VERSION 5.7 ;
  NOWIREEXTENSIONATPIN ON ;
  DIVIDERCHAR "/" ;
  BUSBITCHARS "[]" ;
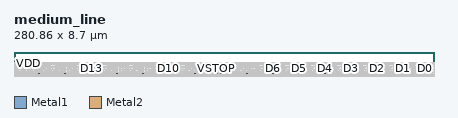
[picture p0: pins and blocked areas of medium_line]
MACRO medium_line
  CLASS BLOCK ;
  FOREIGN medium_line ;
  ORIGIN 0.430 0.430 ;
  SIZE 280.860 BY 8.700 ;
  PIN VSTART
    ANTENNAGATEAREA 0.396000 ;
    PORT
      LAYER Metal1 ;
        RECT 2.200 5.140 4.300 5.500 ;
    END
  END VSTART
  PIN D15
    ANTENNADIFFAREA 0.897600 ;
    PORT
      LAYER Metal1 ;
        RECT 16.200 1.070 16.600 1.470 ;
    END
  END D15
  PIN D14
    ANTENNADIFFAREA 0.897600 ;
    PORT
      LAYER Metal1 ;
        RECT 33.560 1.070 33.960 1.470 ;
    END
  END D14
  PIN D13
    ANTENNADIFFAREA 0.897600 ;
    PORT
      LAYER Metal1 ;
        RECT 50.920 1.070 51.320 1.470 ;
    END
  END D13
  PIN D12
    ANTENNADIFFAREA 0.897600 ;
    PORT
      LAYER Metal1 ;
        RECT 68.280 1.070 68.680 1.470 ;
    END
  END D12
  PIN D11
    ANTENNADIFFAREA 0.897600 ;
    PORT
      LAYER Metal1 ;
        RECT 85.640 1.070 86.040 1.470 ;
    END
  END D11
  PIN D10
    ANTENNADIFFAREA 0.897600 ;
    PORT
      LAYER Metal1 ;
        RECT 103.000 1.070 103.400 1.470 ;
    END
  END D10
  PIN D9
    ANTENNADIFFAREA 0.897600 ;
    PORT
      LAYER Metal1 ;
        RECT 120.360 1.070 120.760 1.470 ;
    END
  END D9
  PIN D8
    ANTENNADIFFAREA 0.897600 ;
    PORT
      LAYER Metal1 ;
        RECT 137.720 1.070 138.120 1.470 ;
    END
  END D8
  PIN D7
    ANTENNADIFFAREA 0.897600 ;
    PORT
      LAYER Metal1 ;
        RECT 155.080 1.070 155.480 1.470 ;
    END
  END D7
  PIN D6
    ANTENNADIFFAREA 0.897600 ;
    PORT
      LAYER Metal1 ;
        RECT 172.440 1.070 172.840 1.470 ;
    END
  END D6
  PIN D5
    ANTENNADIFFAREA 0.897600 ;
    PORT
      LAYER Metal1 ;
        RECT 189.800 1.070 190.200 1.470 ;
    END
  END D5
  PIN D4
    ANTENNADIFFAREA 0.897600 ;
    PORT
      LAYER Metal1 ;
        RECT 207.160 1.070 207.560 1.470 ;
    END
  END D4
  PIN D3
    ANTENNADIFFAREA 0.897600 ;
    PORT
      LAYER Metal1 ;
        RECT 224.520 1.070 224.920 1.470 ;
    END
  END D3
  PIN D2
    ANTENNADIFFAREA 0.897600 ;
    PORT
      LAYER Metal1 ;
        RECT 241.880 1.070 242.280 1.470 ;
    END
  END D2
  PIN D1
    ANTENNADIFFAREA 0.897600 ;
    PORT
      LAYER Metal1 ;
        RECT 259.240 1.070 259.640 1.470 ;
    END
  END D1
  PIN D0
    ANTENNADIFFAREA 0.897600 ;
    PORT
      LAYER Metal1 ;
        RECT 276.600 1.070 277.000 1.470 ;
    END
  END D0
  PIN VSTOP
    ANTENNAGATEAREA 10.808000 ;
    PORT
      LAYER Metal2 ;
        RECT 135.000 1.500 135.400 1.720 ;
    END
  END VSTOP
  PIN VDD
    USE POWER ;
    PORT
      LAYER Metal1 ;
        RECT 5.000 7.740 5.400 8.040 ;
    END
  END VDD
  PIN VSS
    USE GROUND ;
    PORT
      LAYER Metal1 ;
        RECT 5.000 3.720 5.400 4.120 ;
    END
  END VSS
  OBS
      LAYER Nwell ;
        RECT -0.430 5.680 280.430 8.270 ;
      LAYER Pwell ;
        RECT -0.430 2.160 280.430 5.680 ;
      LAYER Nwell ;
        RECT -0.430 2.035 5.985 2.160 ;
      LAYER Pwell ;
        RECT 5.985 2.035 7.240 2.160 ;
      LAYER Nwell ;
        RECT 7.240 2.035 23.345 2.160 ;
      LAYER Pwell ;
        RECT 23.345 2.035 24.600 2.160 ;
      LAYER Nwell ;
        RECT 24.600 2.035 40.705 2.160 ;
      LAYER Pwell ;
        RECT 40.705 2.035 41.960 2.160 ;
      LAYER Nwell ;
        RECT 41.960 2.035 58.065 2.160 ;
      LAYER Pwell ;
        RECT 58.065 2.035 59.320 2.160 ;
      LAYER Nwell ;
        RECT 59.320 2.035 75.425 2.160 ;
      LAYER Pwell ;
        RECT 75.425 2.035 76.680 2.160 ;
      LAYER Nwell ;
        RECT 76.680 2.035 92.785 2.160 ;
      LAYER Pwell ;
        RECT 92.785 2.035 94.040 2.160 ;
      LAYER Nwell ;
        RECT 94.040 2.035 110.145 2.160 ;
      LAYER Pwell ;
        RECT 110.145 2.035 111.400 2.160 ;
      LAYER Nwell ;
        RECT 111.400 2.035 127.505 2.160 ;
      LAYER Pwell ;
        RECT 127.505 2.035 128.760 2.160 ;
      LAYER Nwell ;
        RECT 128.760 2.035 144.865 2.160 ;
      LAYER Pwell ;
        RECT 144.865 2.035 146.120 2.160 ;
      LAYER Nwell ;
        RECT 146.120 2.035 162.225 2.160 ;
      LAYER Pwell ;
        RECT 162.225 2.035 163.480 2.160 ;
      LAYER Nwell ;
        RECT 163.480 2.035 179.585 2.160 ;
      LAYER Pwell ;
        RECT 179.585 2.035 180.840 2.160 ;
      LAYER Nwell ;
        RECT 180.840 2.035 196.945 2.160 ;
      LAYER Pwell ;
        RECT 196.945 2.035 198.200 2.160 ;
      LAYER Nwell ;
        RECT 198.200 2.035 214.305 2.160 ;
      LAYER Pwell ;
        RECT 214.305 2.035 215.560 2.160 ;
      LAYER Nwell ;
        RECT 215.560 2.035 231.665 2.160 ;
      LAYER Pwell ;
        RECT 231.665 2.035 232.920 2.160 ;
      LAYER Nwell ;
        RECT 232.920 2.035 249.025 2.160 ;
      LAYER Pwell ;
        RECT 249.025 2.035 250.280 2.160 ;
      LAYER Nwell ;
        RECT 250.280 2.035 266.385 2.160 ;
      LAYER Pwell ;
        RECT 266.385 2.035 267.640 2.160 ;
      LAYER Nwell ;
        RECT 267.640 2.035 280.430 2.160 ;
        RECT -0.430 -0.430 280.430 2.035 ;
      LAYER Metal1 ;
        RECT 0.000 8.040 280.000 8.140 ;
        RECT 0.000 7.740 5.000 8.040 ;
        RECT 5.400 7.740 280.000 8.040 ;
        RECT 0.000 7.540 280.000 7.740 ;
        RECT 0.370 5.840 0.710 7.540 ;
        RECT 2.580 7.205 2.920 7.540 ;
        RECT 7.560 7.205 7.900 7.540 ;
        RECT 12.840 7.095 13.180 7.540 ;
        RECT 1.340 6.325 1.680 7.025 ;
        RECT 1.340 5.985 4.360 6.325 ;
        RECT 0.370 4.220 0.710 5.110 ;
        RECT 1.340 4.590 1.680 5.985 ;
        RECT 4.815 5.725 5.045 7.080 ;
        RECT 5.480 6.795 6.885 7.025 ;
        RECT 2.025 5.500 4.450 5.520 ;
        RECT 2.025 5.140 2.200 5.500 ;
        RECT 4.300 5.140 4.450 5.500 ;
        RECT 2.025 5.120 4.450 5.140 ;
        RECT 4.815 5.385 6.425 5.725 ;
        RECT 6.655 5.670 6.885 6.795 ;
        RECT 9.995 5.885 10.380 7.080 ;
        RECT 10.815 6.385 11.045 7.080 ;
        RECT 14.490 6.630 14.875 7.115 ;
        RECT 10.815 6.155 12.785 6.385 ;
        RECT 13.085 6.250 14.875 6.630 ;
        RECT 6.655 5.440 9.210 5.670 ;
        RECT 9.995 5.455 12.175 5.885 ;
        RECT 12.465 5.545 12.785 6.155 ;
        RECT 4.815 4.690 5.200 5.385 ;
        RECT 6.655 4.920 6.885 5.440 ;
        RECT 5.580 4.690 6.885 4.920 ;
        RECT 9.995 4.635 10.225 5.455 ;
        RECT 12.465 5.315 14.250 5.545 ;
        RECT 12.465 4.975 12.785 5.315 ;
        RECT 10.815 4.635 12.785 4.975 ;
        RECT 2.680 4.220 3.020 4.555 ;
        RECT 7.760 4.220 8.100 4.555 ;
        RECT 13.235 4.220 13.465 4.610 ;
        RECT 14.645 4.595 14.875 6.250 ;
        RECT 15.510 5.850 15.850 7.540 ;
        RECT 16.630 5.850 16.970 7.540 ;
        RECT 17.750 5.850 18.090 7.540 ;
        RECT 19.940 7.205 20.280 7.540 ;
        RECT 24.920 7.205 25.260 7.540 ;
        RECT 30.200 7.095 30.540 7.540 ;
        RECT 18.700 6.325 19.040 7.025 ;
        RECT 18.700 5.985 21.720 6.325 ;
        RECT 15.510 4.220 15.850 5.105 ;
        RECT 16.630 4.220 16.970 5.105 ;
        RECT 17.750 4.220 18.090 5.105 ;
        RECT 18.700 4.590 19.040 5.985 ;
        RECT 22.175 5.725 22.405 7.080 ;
        RECT 22.840 6.795 24.245 7.025 ;
        RECT 19.385 5.120 21.810 5.520 ;
        RECT 22.175 5.385 23.785 5.725 ;
        RECT 24.015 5.670 24.245 6.795 ;
        RECT 27.355 5.885 27.740 7.080 ;
        RECT 28.175 6.385 28.405 7.080 ;
        RECT 31.850 6.630 32.235 7.115 ;
        RECT 28.175 6.155 30.145 6.385 ;
        RECT 30.445 6.250 32.235 6.630 ;
        RECT 24.015 5.440 26.570 5.670 ;
        RECT 27.355 5.455 29.535 5.885 ;
        RECT 29.825 5.545 30.145 6.155 ;
        RECT 22.175 4.690 22.560 5.385 ;
        RECT 24.015 4.920 24.245 5.440 ;
        RECT 22.940 4.690 24.245 4.920 ;
        RECT 27.355 4.635 27.585 5.455 ;
        RECT 29.825 5.315 31.610 5.545 ;
        RECT 29.825 4.975 30.145 5.315 ;
        RECT 28.175 4.635 30.145 4.975 ;
        RECT 20.040 4.220 20.380 4.555 ;
        RECT 25.120 4.220 25.460 4.555 ;
        RECT 30.595 4.220 30.825 4.610 ;
        RECT 32.005 4.595 32.235 6.250 ;
        RECT 32.870 5.850 33.210 7.540 ;
        RECT 33.990 5.850 34.330 7.540 ;
        RECT 35.110 5.850 35.450 7.540 ;
        RECT 37.300 7.205 37.640 7.540 ;
        RECT 42.280 7.205 42.620 7.540 ;
        RECT 47.560 7.095 47.900 7.540 ;
        RECT 36.060 6.325 36.400 7.025 ;
        RECT 36.060 5.985 39.080 6.325 ;
        RECT 32.870 4.220 33.210 5.105 ;
        RECT 33.990 4.220 34.330 5.105 ;
        RECT 35.110 4.220 35.450 5.105 ;
        RECT 36.060 4.590 36.400 5.985 ;
        RECT 39.535 5.725 39.765 7.080 ;
        RECT 40.200 6.795 41.605 7.025 ;
        RECT 36.745 5.120 39.170 5.520 ;
        RECT 39.535 5.385 41.145 5.725 ;
        RECT 41.375 5.670 41.605 6.795 ;
        RECT 44.715 5.885 45.100 7.080 ;
        RECT 45.535 6.385 45.765 7.080 ;
        RECT 49.210 6.630 49.595 7.115 ;
        RECT 45.535 6.155 47.505 6.385 ;
        RECT 47.805 6.250 49.595 6.630 ;
        RECT 41.375 5.440 43.930 5.670 ;
        RECT 44.715 5.455 46.895 5.885 ;
        RECT 47.185 5.545 47.505 6.155 ;
        RECT 39.535 4.690 39.920 5.385 ;
        RECT 41.375 4.920 41.605 5.440 ;
        RECT 40.300 4.690 41.605 4.920 ;
        RECT 44.715 4.635 44.945 5.455 ;
        RECT 47.185 5.315 48.970 5.545 ;
        RECT 47.185 4.975 47.505 5.315 ;
        RECT 45.535 4.635 47.505 4.975 ;
        RECT 37.400 4.220 37.740 4.555 ;
        RECT 42.480 4.220 42.820 4.555 ;
        RECT 47.955 4.220 48.185 4.610 ;
        RECT 49.365 4.595 49.595 6.250 ;
        RECT 50.230 5.850 50.570 7.540 ;
        RECT 51.350 5.850 51.690 7.540 ;
        RECT 52.470 5.850 52.810 7.540 ;
        RECT 54.660 7.205 55.000 7.540 ;
        RECT 59.640 7.205 59.980 7.540 ;
        RECT 64.920 7.095 65.260 7.540 ;
        RECT 53.420 6.325 53.760 7.025 ;
        RECT 53.420 5.985 56.440 6.325 ;
        RECT 50.230 4.220 50.570 5.105 ;
        RECT 51.350 4.220 51.690 5.105 ;
        RECT 52.470 4.220 52.810 5.105 ;
        RECT 53.420 4.590 53.760 5.985 ;
        RECT 56.895 5.725 57.125 7.080 ;
        RECT 57.560 6.795 58.965 7.025 ;
        RECT 54.105 5.120 56.530 5.520 ;
        RECT 56.895 5.385 58.505 5.725 ;
        RECT 58.735 5.670 58.965 6.795 ;
        RECT 62.075 5.885 62.460 7.080 ;
        RECT 62.895 6.385 63.125 7.080 ;
        RECT 66.570 6.630 66.955 7.115 ;
        RECT 62.895 6.155 64.865 6.385 ;
        RECT 65.165 6.250 66.955 6.630 ;
        RECT 58.735 5.440 61.290 5.670 ;
        RECT 62.075 5.455 64.255 5.885 ;
        RECT 64.545 5.545 64.865 6.155 ;
        RECT 56.895 4.690 57.280 5.385 ;
        RECT 58.735 4.920 58.965 5.440 ;
        RECT 57.660 4.690 58.965 4.920 ;
        RECT 62.075 4.635 62.305 5.455 ;
        RECT 64.545 5.315 66.330 5.545 ;
        RECT 64.545 4.975 64.865 5.315 ;
        RECT 62.895 4.635 64.865 4.975 ;
        RECT 54.760 4.220 55.100 4.555 ;
        RECT 59.840 4.220 60.180 4.555 ;
        RECT 65.315 4.220 65.545 4.610 ;
        RECT 66.725 4.595 66.955 6.250 ;
        RECT 67.590 5.850 67.930 7.540 ;
        RECT 68.710 5.850 69.050 7.540 ;
        RECT 69.830 5.850 70.170 7.540 ;
        RECT 72.020 7.205 72.360 7.540 ;
        RECT 77.000 7.205 77.340 7.540 ;
        RECT 82.280 7.095 82.620 7.540 ;
        RECT 70.780 6.325 71.120 7.025 ;
        RECT 70.780 5.985 73.800 6.325 ;
        RECT 67.590 4.220 67.930 5.105 ;
        RECT 68.710 4.220 69.050 5.105 ;
        RECT 69.830 4.220 70.170 5.105 ;
        RECT 70.780 4.590 71.120 5.985 ;
        RECT 74.255 5.725 74.485 7.080 ;
        RECT 74.920 6.795 76.325 7.025 ;
        RECT 71.465 5.120 73.890 5.520 ;
        RECT 74.255 5.385 75.865 5.725 ;
        RECT 76.095 5.670 76.325 6.795 ;
        RECT 79.435 5.885 79.820 7.080 ;
        RECT 80.255 6.385 80.485 7.080 ;
        RECT 83.930 6.630 84.315 7.115 ;
        RECT 80.255 6.155 82.225 6.385 ;
        RECT 82.525 6.250 84.315 6.630 ;
        RECT 76.095 5.440 78.650 5.670 ;
        RECT 79.435 5.455 81.615 5.885 ;
        RECT 81.905 5.545 82.225 6.155 ;
        RECT 74.255 4.690 74.640 5.385 ;
        RECT 76.095 4.920 76.325 5.440 ;
        RECT 75.020 4.690 76.325 4.920 ;
        RECT 79.435 4.635 79.665 5.455 ;
        RECT 81.905 5.315 83.690 5.545 ;
        RECT 81.905 4.975 82.225 5.315 ;
        RECT 80.255 4.635 82.225 4.975 ;
        RECT 72.120 4.220 72.460 4.555 ;
        RECT 77.200 4.220 77.540 4.555 ;
        RECT 82.675 4.220 82.905 4.610 ;
        RECT 84.085 4.595 84.315 6.250 ;
        RECT 84.950 5.850 85.290 7.540 ;
        RECT 86.070 5.850 86.410 7.540 ;
        RECT 87.190 5.850 87.530 7.540 ;
        RECT 89.380 7.205 89.720 7.540 ;
        RECT 94.360 7.205 94.700 7.540 ;
        RECT 99.640 7.095 99.980 7.540 ;
        RECT 88.140 6.325 88.480 7.025 ;
        RECT 88.140 5.985 91.160 6.325 ;
        RECT 84.950 4.220 85.290 5.105 ;
        RECT 86.070 4.220 86.410 5.105 ;
        RECT 87.190 4.220 87.530 5.105 ;
        RECT 88.140 4.590 88.480 5.985 ;
        RECT 91.615 5.725 91.845 7.080 ;
        RECT 92.280 6.795 93.685 7.025 ;
        RECT 88.825 5.120 91.250 5.520 ;
        RECT 91.615 5.385 93.225 5.725 ;
        RECT 93.455 5.670 93.685 6.795 ;
        RECT 96.795 5.885 97.180 7.080 ;
        RECT 97.615 6.385 97.845 7.080 ;
        RECT 101.290 6.630 101.675 7.115 ;
        RECT 97.615 6.155 99.585 6.385 ;
        RECT 99.885 6.250 101.675 6.630 ;
        RECT 93.455 5.440 96.010 5.670 ;
        RECT 96.795 5.455 98.975 5.885 ;
        RECT 99.265 5.545 99.585 6.155 ;
        RECT 91.615 4.690 92.000 5.385 ;
        RECT 93.455 4.920 93.685 5.440 ;
        RECT 92.380 4.690 93.685 4.920 ;
        RECT 96.795 4.635 97.025 5.455 ;
        RECT 99.265 5.315 101.050 5.545 ;
        RECT 99.265 4.975 99.585 5.315 ;
        RECT 97.615 4.635 99.585 4.975 ;
        RECT 89.480 4.220 89.820 4.555 ;
        RECT 94.560 4.220 94.900 4.555 ;
        RECT 100.035 4.220 100.265 4.610 ;
        RECT 101.445 4.595 101.675 6.250 ;
        RECT 102.310 5.850 102.650 7.540 ;
        RECT 103.430 5.850 103.770 7.540 ;
        RECT 104.550 5.850 104.890 7.540 ;
        RECT 106.740 7.205 107.080 7.540 ;
        RECT 111.720 7.205 112.060 7.540 ;
        RECT 117.000 7.095 117.340 7.540 ;
        RECT 105.500 6.325 105.840 7.025 ;
        RECT 105.500 5.985 108.520 6.325 ;
        RECT 102.310 4.220 102.650 5.105 ;
        RECT 103.430 4.220 103.770 5.105 ;
        RECT 104.550 4.220 104.890 5.105 ;
        RECT 105.500 4.590 105.840 5.985 ;
        RECT 108.975 5.725 109.205 7.080 ;
        RECT 109.640 6.795 111.045 7.025 ;
        RECT 106.185 5.120 108.610 5.520 ;
        RECT 108.975 5.385 110.585 5.725 ;
        RECT 110.815 5.670 111.045 6.795 ;
        RECT 114.155 5.885 114.540 7.080 ;
        RECT 114.975 6.385 115.205 7.080 ;
        RECT 118.650 6.630 119.035 7.115 ;
        RECT 114.975 6.155 116.945 6.385 ;
        RECT 117.245 6.250 119.035 6.630 ;
        RECT 110.815 5.440 113.370 5.670 ;
        RECT 114.155 5.455 116.335 5.885 ;
        RECT 116.625 5.545 116.945 6.155 ;
        RECT 108.975 4.690 109.360 5.385 ;
        RECT 110.815 4.920 111.045 5.440 ;
        RECT 109.740 4.690 111.045 4.920 ;
        RECT 114.155 4.635 114.385 5.455 ;
        RECT 116.625 5.315 118.410 5.545 ;
        RECT 116.625 4.975 116.945 5.315 ;
        RECT 114.975 4.635 116.945 4.975 ;
        RECT 106.840 4.220 107.180 4.555 ;
        RECT 111.920 4.220 112.260 4.555 ;
        RECT 117.395 4.220 117.625 4.610 ;
        RECT 118.805 4.595 119.035 6.250 ;
        RECT 119.670 5.850 120.010 7.540 ;
        RECT 120.790 5.850 121.130 7.540 ;
        RECT 121.910 5.850 122.250 7.540 ;
        RECT 124.100 7.205 124.440 7.540 ;
        RECT 129.080 7.205 129.420 7.540 ;
        RECT 134.360 7.095 134.700 7.540 ;
        RECT 122.860 6.325 123.200 7.025 ;
        RECT 122.860 5.985 125.880 6.325 ;
        RECT 119.670 4.220 120.010 5.105 ;
        RECT 120.790 4.220 121.130 5.105 ;
        RECT 121.910 4.220 122.250 5.105 ;
        RECT 122.860 4.590 123.200 5.985 ;
        RECT 126.335 5.725 126.565 7.080 ;
        RECT 127.000 6.795 128.405 7.025 ;
        RECT 123.545 5.120 125.970 5.520 ;
        RECT 126.335 5.385 127.945 5.725 ;
        RECT 128.175 5.670 128.405 6.795 ;
        RECT 131.515 5.885 131.900 7.080 ;
        RECT 132.335 6.385 132.565 7.080 ;
        RECT 136.010 6.630 136.395 7.115 ;
        RECT 132.335 6.155 134.305 6.385 ;
        RECT 134.605 6.250 136.395 6.630 ;
        RECT 128.175 5.440 130.730 5.670 ;
        RECT 131.515 5.455 133.695 5.885 ;
        RECT 133.985 5.545 134.305 6.155 ;
        RECT 126.335 4.690 126.720 5.385 ;
        RECT 128.175 4.920 128.405 5.440 ;
        RECT 127.100 4.690 128.405 4.920 ;
        RECT 131.515 4.635 131.745 5.455 ;
        RECT 133.985 5.315 135.770 5.545 ;
        RECT 133.985 4.975 134.305 5.315 ;
        RECT 132.335 4.635 134.305 4.975 ;
        RECT 124.200 4.220 124.540 4.555 ;
        RECT 129.280 4.220 129.620 4.555 ;
        RECT 134.755 4.220 134.985 4.610 ;
        RECT 136.165 4.595 136.395 6.250 ;
        RECT 137.030 5.850 137.370 7.540 ;
        RECT 138.150 5.850 138.490 7.540 ;
        RECT 139.270 5.850 139.610 7.540 ;
        RECT 141.460 7.205 141.800 7.540 ;
        RECT 146.440 7.205 146.780 7.540 ;
        RECT 151.720 7.095 152.060 7.540 ;
        RECT 140.220 6.325 140.560 7.025 ;
        RECT 140.220 5.985 143.240 6.325 ;
        RECT 137.030 4.220 137.370 5.105 ;
        RECT 138.150 4.220 138.490 5.105 ;
        RECT 139.270 4.220 139.610 5.105 ;
        RECT 140.220 4.590 140.560 5.985 ;
        RECT 143.695 5.725 143.925 7.080 ;
        RECT 144.360 6.795 145.765 7.025 ;
        RECT 140.905 5.120 143.330 5.520 ;
        RECT 143.695 5.385 145.305 5.725 ;
        RECT 145.535 5.670 145.765 6.795 ;
        RECT 148.875 5.885 149.260 7.080 ;
        RECT 149.695 6.385 149.925 7.080 ;
        RECT 153.370 6.630 153.755 7.115 ;
        RECT 149.695 6.155 151.665 6.385 ;
        RECT 151.965 6.250 153.755 6.630 ;
        RECT 145.535 5.440 148.090 5.670 ;
        RECT 148.875 5.455 151.055 5.885 ;
        RECT 151.345 5.545 151.665 6.155 ;
        RECT 143.695 4.690 144.080 5.385 ;
        RECT 145.535 4.920 145.765 5.440 ;
        RECT 144.460 4.690 145.765 4.920 ;
        RECT 148.875 4.635 149.105 5.455 ;
        RECT 151.345 5.315 153.130 5.545 ;
        RECT 151.345 4.975 151.665 5.315 ;
        RECT 149.695 4.635 151.665 4.975 ;
        RECT 141.560 4.220 141.900 4.555 ;
        RECT 146.640 4.220 146.980 4.555 ;
        RECT 152.115 4.220 152.345 4.610 ;
        RECT 153.525 4.595 153.755 6.250 ;
        RECT 154.390 5.850 154.730 7.540 ;
        RECT 155.510 5.850 155.850 7.540 ;
        RECT 156.630 5.850 156.970 7.540 ;
        RECT 158.820 7.205 159.160 7.540 ;
        RECT 163.800 7.205 164.140 7.540 ;
        RECT 169.080 7.095 169.420 7.540 ;
        RECT 157.580 6.325 157.920 7.025 ;
        RECT 157.580 5.985 160.600 6.325 ;
        RECT 154.390 4.220 154.730 5.105 ;
        RECT 155.510 4.220 155.850 5.105 ;
        RECT 156.630 4.220 156.970 5.105 ;
        RECT 157.580 4.590 157.920 5.985 ;
        RECT 161.055 5.725 161.285 7.080 ;
        RECT 161.720 6.795 163.125 7.025 ;
        RECT 158.265 5.120 160.690 5.520 ;
        RECT 161.055 5.385 162.665 5.725 ;
        RECT 162.895 5.670 163.125 6.795 ;
        RECT 166.235 5.885 166.620 7.080 ;
        RECT 167.055 6.385 167.285 7.080 ;
        RECT 170.730 6.630 171.115 7.115 ;
        RECT 167.055 6.155 169.025 6.385 ;
        RECT 169.325 6.250 171.115 6.630 ;
        RECT 162.895 5.440 165.450 5.670 ;
        RECT 166.235 5.455 168.415 5.885 ;
        RECT 168.705 5.545 169.025 6.155 ;
        RECT 161.055 4.690 161.440 5.385 ;
        RECT 162.895 4.920 163.125 5.440 ;
        RECT 161.820 4.690 163.125 4.920 ;
        RECT 166.235 4.635 166.465 5.455 ;
        RECT 168.705 5.315 170.490 5.545 ;
        RECT 168.705 4.975 169.025 5.315 ;
        RECT 167.055 4.635 169.025 4.975 ;
        RECT 158.920 4.220 159.260 4.555 ;
        RECT 164.000 4.220 164.340 4.555 ;
        RECT 169.475 4.220 169.705 4.610 ;
        RECT 170.885 4.595 171.115 6.250 ;
        RECT 171.750 5.850 172.090 7.540 ;
        RECT 172.870 5.850 173.210 7.540 ;
        RECT 173.990 5.850 174.330 7.540 ;
        RECT 176.180 7.205 176.520 7.540 ;
        RECT 181.160 7.205 181.500 7.540 ;
        RECT 186.440 7.095 186.780 7.540 ;
        RECT 174.940 6.325 175.280 7.025 ;
        RECT 174.940 5.985 177.960 6.325 ;
        RECT 171.750 4.220 172.090 5.105 ;
        RECT 172.870 4.220 173.210 5.105 ;
        RECT 173.990 4.220 174.330 5.105 ;
        RECT 174.940 4.590 175.280 5.985 ;
        RECT 178.415 5.725 178.645 7.080 ;
        RECT 179.080 6.795 180.485 7.025 ;
        RECT 175.625 5.120 178.050 5.520 ;
        RECT 178.415 5.385 180.025 5.725 ;
        RECT 180.255 5.670 180.485 6.795 ;
        RECT 183.595 5.885 183.980 7.080 ;
        RECT 184.415 6.385 184.645 7.080 ;
        RECT 188.090 6.630 188.475 7.115 ;
        RECT 184.415 6.155 186.385 6.385 ;
        RECT 186.685 6.250 188.475 6.630 ;
        RECT 180.255 5.440 182.810 5.670 ;
        RECT 183.595 5.455 185.775 5.885 ;
        RECT 186.065 5.545 186.385 6.155 ;
        RECT 178.415 4.690 178.800 5.385 ;
        RECT 180.255 4.920 180.485 5.440 ;
        RECT 179.180 4.690 180.485 4.920 ;
        RECT 183.595 4.635 183.825 5.455 ;
        RECT 186.065 5.315 187.850 5.545 ;
        RECT 186.065 4.975 186.385 5.315 ;
        RECT 184.415 4.635 186.385 4.975 ;
        RECT 176.280 4.220 176.620 4.555 ;
        RECT 181.360 4.220 181.700 4.555 ;
        RECT 186.835 4.220 187.065 4.610 ;
        RECT 188.245 4.595 188.475 6.250 ;
        RECT 189.110 5.850 189.450 7.540 ;
        RECT 190.230 5.850 190.570 7.540 ;
        RECT 191.350 5.850 191.690 7.540 ;
        RECT 193.540 7.205 193.880 7.540 ;
        RECT 198.520 7.205 198.860 7.540 ;
        RECT 203.800 7.095 204.140 7.540 ;
        RECT 192.300 6.325 192.640 7.025 ;
        RECT 192.300 5.985 195.320 6.325 ;
        RECT 189.110 4.220 189.450 5.105 ;
        RECT 190.230 4.220 190.570 5.105 ;
        RECT 191.350 4.220 191.690 5.105 ;
        RECT 192.300 4.590 192.640 5.985 ;
        RECT 195.775 5.725 196.005 7.080 ;
        RECT 196.440 6.795 197.845 7.025 ;
        RECT 192.985 5.120 195.410 5.520 ;
        RECT 195.775 5.385 197.385 5.725 ;
        RECT 197.615 5.670 197.845 6.795 ;
        RECT 200.955 5.885 201.340 7.080 ;
        RECT 201.775 6.385 202.005 7.080 ;
        RECT 205.450 6.630 205.835 7.115 ;
        RECT 201.775 6.155 203.745 6.385 ;
        RECT 204.045 6.250 205.835 6.630 ;
        RECT 197.615 5.440 200.170 5.670 ;
        RECT 200.955 5.455 203.135 5.885 ;
        RECT 203.425 5.545 203.745 6.155 ;
        RECT 195.775 4.690 196.160 5.385 ;
        RECT 197.615 4.920 197.845 5.440 ;
        RECT 196.540 4.690 197.845 4.920 ;
        RECT 200.955 4.635 201.185 5.455 ;
        RECT 203.425 5.315 205.210 5.545 ;
        RECT 203.425 4.975 203.745 5.315 ;
        RECT 201.775 4.635 203.745 4.975 ;
        RECT 193.640 4.220 193.980 4.555 ;
        RECT 198.720 4.220 199.060 4.555 ;
        RECT 204.195 4.220 204.425 4.610 ;
        RECT 205.605 4.595 205.835 6.250 ;
        RECT 206.470 5.850 206.810 7.540 ;
        RECT 207.590 5.850 207.930 7.540 ;
        RECT 208.710 5.850 209.050 7.540 ;
        RECT 210.900 7.205 211.240 7.540 ;
        RECT 215.880 7.205 216.220 7.540 ;
        RECT 221.160 7.095 221.500 7.540 ;
        RECT 209.660 6.325 210.000 7.025 ;
        RECT 209.660 5.985 212.680 6.325 ;
        RECT 206.470 4.220 206.810 5.105 ;
        RECT 207.590 4.220 207.930 5.105 ;
        RECT 208.710 4.220 209.050 5.105 ;
        RECT 209.660 4.590 210.000 5.985 ;
        RECT 213.135 5.725 213.365 7.080 ;
        RECT 213.800 6.795 215.205 7.025 ;
        RECT 210.345 5.120 212.770 5.520 ;
        RECT 213.135 5.385 214.745 5.725 ;
        RECT 214.975 5.670 215.205 6.795 ;
        RECT 218.315 5.885 218.700 7.080 ;
        RECT 219.135 6.385 219.365 7.080 ;
        RECT 222.810 6.630 223.195 7.115 ;
        RECT 219.135 6.155 221.105 6.385 ;
        RECT 221.405 6.250 223.195 6.630 ;
        RECT 214.975 5.440 217.530 5.670 ;
        RECT 218.315 5.455 220.495 5.885 ;
        RECT 220.785 5.545 221.105 6.155 ;
        RECT 213.135 4.690 213.520 5.385 ;
        RECT 214.975 4.920 215.205 5.440 ;
        RECT 213.900 4.690 215.205 4.920 ;
        RECT 218.315 4.635 218.545 5.455 ;
        RECT 220.785 5.315 222.570 5.545 ;
        RECT 220.785 4.975 221.105 5.315 ;
        RECT 219.135 4.635 221.105 4.975 ;
        RECT 211.000 4.220 211.340 4.555 ;
        RECT 216.080 4.220 216.420 4.555 ;
        RECT 221.555 4.220 221.785 4.610 ;
        RECT 222.965 4.595 223.195 6.250 ;
        RECT 223.830 5.850 224.170 7.540 ;
        RECT 224.950 5.850 225.290 7.540 ;
        RECT 226.070 5.850 226.410 7.540 ;
        RECT 228.260 7.205 228.600 7.540 ;
        RECT 233.240 7.205 233.580 7.540 ;
        RECT 238.520 7.095 238.860 7.540 ;
        RECT 227.020 6.325 227.360 7.025 ;
        RECT 227.020 5.985 230.040 6.325 ;
        RECT 223.830 4.220 224.170 5.105 ;
        RECT 224.950 4.220 225.290 5.105 ;
        RECT 226.070 4.220 226.410 5.105 ;
        RECT 227.020 4.590 227.360 5.985 ;
        RECT 230.495 5.725 230.725 7.080 ;
        RECT 231.160 6.795 232.565 7.025 ;
        RECT 227.705 5.120 230.130 5.520 ;
        RECT 230.495 5.385 232.105 5.725 ;
        RECT 232.335 5.670 232.565 6.795 ;
        RECT 235.675 5.885 236.060 7.080 ;
        RECT 236.495 6.385 236.725 7.080 ;
        RECT 240.170 6.630 240.555 7.115 ;
        RECT 236.495 6.155 238.465 6.385 ;
        RECT 238.765 6.250 240.555 6.630 ;
        RECT 232.335 5.440 234.890 5.670 ;
        RECT 235.675 5.455 237.855 5.885 ;
        RECT 238.145 5.545 238.465 6.155 ;
        RECT 230.495 4.690 230.880 5.385 ;
        RECT 232.335 4.920 232.565 5.440 ;
        RECT 231.260 4.690 232.565 4.920 ;
        RECT 235.675 4.635 235.905 5.455 ;
        RECT 238.145 5.315 239.930 5.545 ;
        RECT 238.145 4.975 238.465 5.315 ;
        RECT 236.495 4.635 238.465 4.975 ;
        RECT 228.360 4.220 228.700 4.555 ;
        RECT 233.440 4.220 233.780 4.555 ;
        RECT 238.915 4.220 239.145 4.610 ;
        RECT 240.325 4.595 240.555 6.250 ;
        RECT 241.190 5.850 241.530 7.540 ;
        RECT 242.310 5.850 242.650 7.540 ;
        RECT 243.430 5.850 243.770 7.540 ;
        RECT 245.620 7.205 245.960 7.540 ;
        RECT 250.600 7.205 250.940 7.540 ;
        RECT 255.880 7.095 256.220 7.540 ;
        RECT 244.380 6.325 244.720 7.025 ;
        RECT 244.380 5.985 247.400 6.325 ;
        RECT 241.190 4.220 241.530 5.105 ;
        RECT 242.310 4.220 242.650 5.105 ;
        RECT 243.430 4.220 243.770 5.105 ;
        RECT 244.380 4.590 244.720 5.985 ;
        RECT 247.855 5.725 248.085 7.080 ;
        RECT 248.520 6.795 249.925 7.025 ;
        RECT 245.065 5.120 247.490 5.520 ;
        RECT 247.855 5.385 249.465 5.725 ;
        RECT 249.695 5.670 249.925 6.795 ;
        RECT 253.035 5.885 253.420 7.080 ;
        RECT 253.855 6.385 254.085 7.080 ;
        RECT 257.530 6.630 257.915 7.115 ;
        RECT 253.855 6.155 255.825 6.385 ;
        RECT 256.125 6.250 257.915 6.630 ;
        RECT 249.695 5.440 252.250 5.670 ;
        RECT 253.035 5.455 255.215 5.885 ;
        RECT 255.505 5.545 255.825 6.155 ;
        RECT 247.855 4.690 248.240 5.385 ;
        RECT 249.695 4.920 249.925 5.440 ;
        RECT 248.620 4.690 249.925 4.920 ;
        RECT 253.035 4.635 253.265 5.455 ;
        RECT 255.505 5.315 257.290 5.545 ;
        RECT 255.505 4.975 255.825 5.315 ;
        RECT 253.855 4.635 255.825 4.975 ;
        RECT 245.720 4.220 246.060 4.555 ;
        RECT 250.800 4.220 251.140 4.555 ;
        RECT 256.275 4.220 256.505 4.610 ;
        RECT 257.685 4.595 257.915 6.250 ;
        RECT 258.550 5.850 258.890 7.540 ;
        RECT 259.670 5.850 260.010 7.540 ;
        RECT 260.790 5.850 261.130 7.540 ;
        RECT 262.980 7.205 263.320 7.540 ;
        RECT 267.960 7.205 268.300 7.540 ;
        RECT 273.240 7.095 273.580 7.540 ;
        RECT 261.740 6.325 262.080 7.025 ;
        RECT 261.740 5.985 264.760 6.325 ;
        RECT 258.550 4.220 258.890 5.105 ;
        RECT 259.670 4.220 260.010 5.105 ;
        RECT 260.790 4.220 261.130 5.105 ;
        RECT 261.740 4.590 262.080 5.985 ;
        RECT 265.215 5.725 265.445 7.080 ;
        RECT 265.880 6.795 267.285 7.025 ;
        RECT 262.425 5.120 264.850 5.520 ;
        RECT 265.215 5.385 266.825 5.725 ;
        RECT 267.055 5.670 267.285 6.795 ;
        RECT 270.395 5.885 270.780 7.080 ;
        RECT 271.215 6.385 271.445 7.080 ;
        RECT 274.890 6.630 275.275 7.115 ;
        RECT 271.215 6.155 273.185 6.385 ;
        RECT 273.485 6.250 275.275 6.630 ;
        RECT 267.055 5.440 269.610 5.670 ;
        RECT 270.395 5.455 272.575 5.885 ;
        RECT 272.865 5.545 273.185 6.155 ;
        RECT 265.215 4.690 265.600 5.385 ;
        RECT 267.055 4.920 267.285 5.440 ;
        RECT 265.980 4.690 267.285 4.920 ;
        RECT 270.395 4.635 270.625 5.455 ;
        RECT 272.865 5.315 274.650 5.545 ;
        RECT 272.865 4.975 273.185 5.315 ;
        RECT 271.215 4.635 273.185 4.975 ;
        RECT 263.080 4.220 263.420 4.555 ;
        RECT 268.160 4.220 268.500 4.555 ;
        RECT 273.635 4.220 273.865 4.610 ;
        RECT 275.045 4.595 275.275 6.250 ;
        RECT 275.910 5.850 276.250 7.540 ;
        RECT 277.030 5.850 277.370 7.540 ;
        RECT 278.150 5.850 278.490 7.540 ;
        RECT 279.250 5.840 279.590 7.540 ;
        RECT 275.910 4.220 276.250 5.105 ;
        RECT 277.030 4.220 277.370 5.105 ;
        RECT 278.150 4.220 278.490 5.105 ;
        RECT 279.250 4.220 279.590 5.110 ;
        RECT 0.000 4.120 280.000 4.220 ;
        RECT 0.000 3.720 5.000 4.120 ;
        RECT 5.400 3.720 280.000 4.120 ;
        RECT 0.000 3.620 280.000 3.720 ;
        RECT 0.370 2.730 0.710 3.620 ;
        RECT 1.365 2.640 1.595 3.110 ;
        RECT 2.430 2.870 2.770 3.620 ;
        RECT 1.365 2.410 3.265 2.640 ;
        RECT 0.370 0.300 0.710 2.000 ;
        RECT 1.770 1.770 2.710 2.150 ;
        RECT 3.035 1.450 3.265 2.410 ;
        RECT 3.605 2.595 3.835 3.110 ;
        RECT 4.270 2.830 4.610 3.620 ;
        RECT 4.965 3.160 7.515 3.390 ;
        RECT 8.910 3.335 9.250 3.620 ;
        RECT 4.965 2.595 5.195 3.160 ;
        RECT 3.605 2.365 5.195 2.595 ;
        RECT 4.965 1.830 5.195 2.365 ;
        RECT 1.465 1.220 3.265 1.450 ;
        RECT 1.465 0.765 1.695 1.220 ;
        RECT 2.430 0.300 2.770 0.990 ;
        RECT 3.035 0.940 3.265 1.220 ;
        RECT 3.505 1.595 5.195 1.830 ;
        RECT 3.505 1.210 3.735 1.595 ;
        RECT 3.965 1.035 5.240 1.270 ;
        RECT 5.690 1.210 6.095 2.710 ;
        RECT 6.445 1.680 6.790 2.930 ;
        RECT 7.285 2.140 7.515 3.160 ;
        RECT 10.250 2.600 10.590 3.060 ;
        RECT 8.250 2.370 10.590 2.600 ;
        RECT 7.285 1.910 9.990 2.140 ;
        RECT 6.445 1.450 9.530 1.680 ;
        RECT 3.965 0.940 4.195 1.035 ;
        RECT 3.035 0.705 4.195 0.940 ;
        RECT 5.010 0.760 5.240 1.035 ;
        RECT 6.730 0.990 7.070 1.450 ;
        RECT 4.425 0.300 4.655 0.735 ;
        RECT 5.010 0.530 7.710 0.760 ;
        RECT 8.750 0.300 9.090 1.220 ;
        RECT 9.760 0.760 9.990 1.910 ;
        RECT 10.245 0.990 10.590 2.370 ;
        RECT 10.840 0.760 11.070 2.695 ;
        RECT 11.370 2.025 11.710 3.060 ;
        RECT 13.605 2.815 13.835 3.620 ;
        RECT 14.725 2.520 14.990 3.165 ;
        RECT 15.545 3.030 15.775 3.620 ;
        RECT 12.890 2.420 14.990 2.520 ;
        RECT 12.890 2.290 16.215 2.420 ;
        RECT 14.765 2.080 16.215 2.290 ;
        RECT 11.370 1.790 14.470 2.025 ;
        RECT 11.370 0.990 11.710 1.790 ;
        RECT 9.760 0.530 12.450 0.760 ;
        RECT 13.745 0.300 13.975 1.285 ;
        RECT 14.765 0.890 14.995 2.080 ;
        RECT 16.590 1.590 16.970 3.370 ;
        RECT 17.750 2.735 18.090 3.620 ;
        RECT 18.725 2.640 18.955 3.110 ;
        RECT 19.790 2.870 20.130 3.620 ;
        RECT 18.725 2.410 20.625 2.640 ;
        RECT 15.955 1.470 16.970 1.590 ;
        RECT 15.485 0.300 15.715 1.285 ;
        RECT 15.955 1.070 16.200 1.470 ;
        RECT 16.600 1.070 16.970 1.470 ;
        RECT 15.955 0.945 16.970 1.070 ;
        RECT 17.750 0.300 18.090 1.990 ;
        RECT 19.130 1.770 20.070 2.150 ;
        RECT 20.395 1.450 20.625 2.410 ;
        RECT 20.965 2.595 21.195 3.110 ;
        RECT 21.630 2.830 21.970 3.620 ;
        RECT 22.325 3.160 24.875 3.390 ;
        RECT 26.270 3.335 26.610 3.620 ;
        RECT 22.325 2.595 22.555 3.160 ;
        RECT 20.965 2.365 22.555 2.595 ;
        RECT 22.325 1.830 22.555 2.365 ;
        RECT 18.825 1.220 20.625 1.450 ;
        RECT 18.825 0.765 19.055 1.220 ;
        RECT 19.790 0.300 20.130 0.990 ;
        RECT 20.395 0.940 20.625 1.220 ;
        RECT 20.865 1.595 22.555 1.830 ;
        RECT 20.865 1.210 21.095 1.595 ;
        RECT 21.325 1.035 22.600 1.270 ;
        RECT 23.050 1.210 23.455 2.710 ;
        RECT 23.805 1.680 24.150 2.930 ;
        RECT 24.645 2.140 24.875 3.160 ;
        RECT 27.610 2.600 27.950 3.060 ;
        RECT 25.610 2.370 27.950 2.600 ;
        RECT 24.645 1.910 27.350 2.140 ;
        RECT 23.805 1.450 26.890 1.680 ;
        RECT 21.325 0.940 21.555 1.035 ;
        RECT 20.395 0.705 21.555 0.940 ;
        RECT 22.370 0.760 22.600 1.035 ;
        RECT 24.090 0.990 24.430 1.450 ;
        RECT 21.785 0.300 22.015 0.735 ;
        RECT 22.370 0.530 25.070 0.760 ;
        RECT 26.110 0.300 26.450 1.220 ;
        RECT 27.120 0.760 27.350 1.910 ;
        RECT 27.605 0.990 27.950 2.370 ;
        RECT 28.200 0.760 28.430 2.695 ;
        RECT 28.730 2.025 29.070 3.060 ;
        RECT 30.965 2.815 31.195 3.620 ;
        RECT 32.085 2.520 32.350 3.165 ;
        RECT 32.905 3.030 33.135 3.620 ;
        RECT 30.250 2.420 32.350 2.520 ;
        RECT 30.250 2.290 33.575 2.420 ;
        RECT 32.125 2.080 33.575 2.290 ;
        RECT 28.730 1.790 31.830 2.025 ;
        RECT 28.730 0.990 29.070 1.790 ;
        RECT 27.120 0.530 29.810 0.760 ;
        RECT 31.105 0.300 31.335 1.285 ;
        RECT 32.125 0.890 32.355 2.080 ;
        RECT 33.950 1.590 34.330 3.370 ;
        RECT 35.110 2.735 35.450 3.620 ;
        RECT 36.085 2.640 36.315 3.110 ;
        RECT 37.150 2.870 37.490 3.620 ;
        RECT 36.085 2.410 37.985 2.640 ;
        RECT 33.315 1.470 34.330 1.590 ;
        RECT 32.845 0.300 33.075 1.285 ;
        RECT 33.315 1.070 33.560 1.470 ;
        RECT 33.960 1.070 34.330 1.470 ;
        RECT 33.315 0.945 34.330 1.070 ;
        RECT 35.110 0.300 35.450 1.990 ;
        RECT 36.490 1.770 37.430 2.150 ;
        RECT 37.755 1.450 37.985 2.410 ;
        RECT 38.325 2.595 38.555 3.110 ;
        RECT 38.990 2.830 39.330 3.620 ;
        RECT 39.685 3.160 42.235 3.390 ;
        RECT 43.630 3.335 43.970 3.620 ;
        RECT 39.685 2.595 39.915 3.160 ;
        RECT 38.325 2.365 39.915 2.595 ;
        RECT 39.685 1.830 39.915 2.365 ;
        RECT 36.185 1.220 37.985 1.450 ;
        RECT 36.185 0.765 36.415 1.220 ;
        RECT 37.150 0.300 37.490 0.990 ;
        RECT 37.755 0.940 37.985 1.220 ;
        RECT 38.225 1.595 39.915 1.830 ;
        RECT 38.225 1.210 38.455 1.595 ;
        RECT 38.685 1.035 39.960 1.270 ;
        RECT 40.410 1.210 40.815 2.710 ;
        RECT 41.165 1.680 41.510 2.930 ;
        RECT 42.005 2.140 42.235 3.160 ;
        RECT 44.970 2.600 45.310 3.060 ;
        RECT 42.970 2.370 45.310 2.600 ;
        RECT 42.005 1.910 44.710 2.140 ;
        RECT 41.165 1.450 44.250 1.680 ;
        RECT 38.685 0.940 38.915 1.035 ;
        RECT 37.755 0.705 38.915 0.940 ;
        RECT 39.730 0.760 39.960 1.035 ;
        RECT 41.450 0.990 41.790 1.450 ;
        RECT 39.145 0.300 39.375 0.735 ;
        RECT 39.730 0.530 42.430 0.760 ;
        RECT 43.470 0.300 43.810 1.220 ;
        RECT 44.480 0.760 44.710 1.910 ;
        RECT 44.965 0.990 45.310 2.370 ;
        RECT 45.560 0.760 45.790 2.695 ;
        RECT 46.090 2.025 46.430 3.060 ;
        RECT 48.325 2.815 48.555 3.620 ;
        RECT 49.445 2.520 49.710 3.165 ;
        RECT 50.265 3.030 50.495 3.620 ;
        RECT 47.610 2.420 49.710 2.520 ;
        RECT 47.610 2.290 50.935 2.420 ;
        RECT 49.485 2.080 50.935 2.290 ;
        RECT 46.090 1.790 49.190 2.025 ;
        RECT 46.090 0.990 46.430 1.790 ;
        RECT 44.480 0.530 47.170 0.760 ;
        RECT 48.465 0.300 48.695 1.285 ;
        RECT 49.485 0.890 49.715 2.080 ;
        RECT 51.310 1.590 51.690 3.370 ;
        RECT 52.470 2.735 52.810 3.620 ;
        RECT 53.445 2.640 53.675 3.110 ;
        RECT 54.510 2.870 54.850 3.620 ;
        RECT 53.445 2.410 55.345 2.640 ;
        RECT 50.675 1.470 51.690 1.590 ;
        RECT 50.205 0.300 50.435 1.285 ;
        RECT 50.675 1.070 50.920 1.470 ;
        RECT 51.320 1.070 51.690 1.470 ;
        RECT 50.675 0.945 51.690 1.070 ;
        RECT 52.470 0.300 52.810 1.990 ;
        RECT 53.850 1.770 54.790 2.150 ;
        RECT 55.115 1.450 55.345 2.410 ;
        RECT 55.685 2.595 55.915 3.110 ;
        RECT 56.350 2.830 56.690 3.620 ;
        RECT 57.045 3.160 59.595 3.390 ;
        RECT 60.990 3.335 61.330 3.620 ;
        RECT 57.045 2.595 57.275 3.160 ;
        RECT 55.685 2.365 57.275 2.595 ;
        RECT 57.045 1.830 57.275 2.365 ;
        RECT 53.545 1.220 55.345 1.450 ;
        RECT 53.545 0.765 53.775 1.220 ;
        RECT 54.510 0.300 54.850 0.990 ;
        RECT 55.115 0.940 55.345 1.220 ;
        RECT 55.585 1.595 57.275 1.830 ;
        RECT 55.585 1.210 55.815 1.595 ;
        RECT 56.045 1.035 57.320 1.270 ;
        RECT 57.770 1.210 58.175 2.710 ;
        RECT 58.525 1.680 58.870 2.930 ;
        RECT 59.365 2.140 59.595 3.160 ;
        RECT 62.330 2.600 62.670 3.060 ;
        RECT 60.330 2.370 62.670 2.600 ;
        RECT 59.365 1.910 62.070 2.140 ;
        RECT 58.525 1.450 61.610 1.680 ;
        RECT 56.045 0.940 56.275 1.035 ;
        RECT 55.115 0.705 56.275 0.940 ;
        RECT 57.090 0.760 57.320 1.035 ;
        RECT 58.810 0.990 59.150 1.450 ;
        RECT 56.505 0.300 56.735 0.735 ;
        RECT 57.090 0.530 59.790 0.760 ;
        RECT 60.830 0.300 61.170 1.220 ;
        RECT 61.840 0.760 62.070 1.910 ;
        RECT 62.325 0.990 62.670 2.370 ;
        RECT 62.920 0.760 63.150 2.695 ;
        RECT 63.450 2.025 63.790 3.060 ;
        RECT 65.685 2.815 65.915 3.620 ;
        RECT 66.805 2.520 67.070 3.165 ;
        RECT 67.625 3.030 67.855 3.620 ;
        RECT 64.970 2.420 67.070 2.520 ;
        RECT 64.970 2.290 68.295 2.420 ;
        RECT 66.845 2.080 68.295 2.290 ;
        RECT 63.450 1.790 66.550 2.025 ;
        RECT 63.450 0.990 63.790 1.790 ;
        RECT 61.840 0.530 64.530 0.760 ;
        RECT 65.825 0.300 66.055 1.285 ;
        RECT 66.845 0.890 67.075 2.080 ;
        RECT 68.670 1.590 69.050 3.370 ;
        RECT 69.830 2.735 70.170 3.620 ;
        RECT 70.805 2.640 71.035 3.110 ;
        RECT 71.870 2.870 72.210 3.620 ;
        RECT 70.805 2.410 72.705 2.640 ;
        RECT 68.035 1.470 69.050 1.590 ;
        RECT 67.565 0.300 67.795 1.285 ;
        RECT 68.035 1.070 68.280 1.470 ;
        RECT 68.680 1.070 69.050 1.470 ;
        RECT 68.035 0.945 69.050 1.070 ;
        RECT 69.830 0.300 70.170 1.990 ;
        RECT 71.210 1.770 72.150 2.150 ;
        RECT 72.475 1.450 72.705 2.410 ;
        RECT 73.045 2.595 73.275 3.110 ;
        RECT 73.710 2.830 74.050 3.620 ;
        RECT 74.405 3.160 76.955 3.390 ;
        RECT 78.350 3.335 78.690 3.620 ;
        RECT 74.405 2.595 74.635 3.160 ;
        RECT 73.045 2.365 74.635 2.595 ;
        RECT 74.405 1.830 74.635 2.365 ;
        RECT 70.905 1.220 72.705 1.450 ;
        RECT 70.905 0.765 71.135 1.220 ;
        RECT 71.870 0.300 72.210 0.990 ;
        RECT 72.475 0.940 72.705 1.220 ;
        RECT 72.945 1.595 74.635 1.830 ;
        RECT 72.945 1.210 73.175 1.595 ;
        RECT 73.405 1.035 74.680 1.270 ;
        RECT 75.130 1.210 75.535 2.710 ;
        RECT 75.885 1.680 76.230 2.930 ;
        RECT 76.725 2.140 76.955 3.160 ;
        RECT 79.690 2.600 80.030 3.060 ;
        RECT 77.690 2.370 80.030 2.600 ;
        RECT 76.725 1.910 79.430 2.140 ;
        RECT 75.885 1.450 78.970 1.680 ;
        RECT 73.405 0.940 73.635 1.035 ;
        RECT 72.475 0.705 73.635 0.940 ;
        RECT 74.450 0.760 74.680 1.035 ;
        RECT 76.170 0.990 76.510 1.450 ;
        RECT 73.865 0.300 74.095 0.735 ;
        RECT 74.450 0.530 77.150 0.760 ;
        RECT 78.190 0.300 78.530 1.220 ;
        RECT 79.200 0.760 79.430 1.910 ;
        RECT 79.685 0.990 80.030 2.370 ;
        RECT 80.280 0.760 80.510 2.695 ;
        RECT 80.810 2.025 81.150 3.060 ;
        RECT 83.045 2.815 83.275 3.620 ;
        RECT 84.165 2.520 84.430 3.165 ;
        RECT 84.985 3.030 85.215 3.620 ;
        RECT 82.330 2.420 84.430 2.520 ;
        RECT 82.330 2.290 85.655 2.420 ;
        RECT 84.205 2.080 85.655 2.290 ;
        RECT 80.810 1.790 83.910 2.025 ;
        RECT 80.810 0.990 81.150 1.790 ;
        RECT 79.200 0.530 81.890 0.760 ;
        RECT 83.185 0.300 83.415 1.285 ;
        RECT 84.205 0.890 84.435 2.080 ;
        RECT 86.030 1.590 86.410 3.370 ;
        RECT 87.190 2.735 87.530 3.620 ;
        RECT 88.165 2.640 88.395 3.110 ;
        RECT 89.230 2.870 89.570 3.620 ;
        RECT 88.165 2.410 90.065 2.640 ;
        RECT 85.395 1.470 86.410 1.590 ;
        RECT 84.925 0.300 85.155 1.285 ;
        RECT 85.395 1.070 85.640 1.470 ;
        RECT 86.040 1.070 86.410 1.470 ;
        RECT 85.395 0.945 86.410 1.070 ;
        RECT 87.190 0.300 87.530 1.990 ;
        RECT 88.570 1.770 89.510 2.150 ;
        RECT 89.835 1.450 90.065 2.410 ;
        RECT 90.405 2.595 90.635 3.110 ;
        RECT 91.070 2.830 91.410 3.620 ;
        RECT 91.765 3.160 94.315 3.390 ;
        RECT 95.710 3.335 96.050 3.620 ;
        RECT 91.765 2.595 91.995 3.160 ;
        RECT 90.405 2.365 91.995 2.595 ;
        RECT 91.765 1.830 91.995 2.365 ;
        RECT 88.265 1.220 90.065 1.450 ;
        RECT 88.265 0.765 88.495 1.220 ;
        RECT 89.230 0.300 89.570 0.990 ;
        RECT 89.835 0.940 90.065 1.220 ;
        RECT 90.305 1.595 91.995 1.830 ;
        RECT 90.305 1.210 90.535 1.595 ;
        RECT 90.765 1.035 92.040 1.270 ;
        RECT 92.490 1.210 92.895 2.710 ;
        RECT 93.245 1.680 93.590 2.930 ;
        RECT 94.085 2.140 94.315 3.160 ;
        RECT 97.050 2.600 97.390 3.060 ;
        RECT 95.050 2.370 97.390 2.600 ;
        RECT 94.085 1.910 96.790 2.140 ;
        RECT 93.245 1.450 96.330 1.680 ;
        RECT 90.765 0.940 90.995 1.035 ;
        RECT 89.835 0.705 90.995 0.940 ;
        RECT 91.810 0.760 92.040 1.035 ;
        RECT 93.530 0.990 93.870 1.450 ;
        RECT 91.225 0.300 91.455 0.735 ;
        RECT 91.810 0.530 94.510 0.760 ;
        RECT 95.550 0.300 95.890 1.220 ;
        RECT 96.560 0.760 96.790 1.910 ;
        RECT 97.045 0.990 97.390 2.370 ;
        RECT 97.640 0.760 97.870 2.695 ;
        RECT 98.170 2.025 98.510 3.060 ;
        RECT 100.405 2.815 100.635 3.620 ;
        RECT 101.525 2.520 101.790 3.165 ;
        RECT 102.345 3.030 102.575 3.620 ;
        RECT 99.690 2.420 101.790 2.520 ;
        RECT 99.690 2.290 103.015 2.420 ;
        RECT 101.565 2.080 103.015 2.290 ;
        RECT 98.170 1.790 101.270 2.025 ;
        RECT 98.170 0.990 98.510 1.790 ;
        RECT 96.560 0.530 99.250 0.760 ;
        RECT 100.545 0.300 100.775 1.285 ;
        RECT 101.565 0.890 101.795 2.080 ;
        RECT 103.390 1.590 103.770 3.370 ;
        RECT 104.550 2.735 104.890 3.620 ;
        RECT 105.525 2.640 105.755 3.110 ;
        RECT 106.590 2.870 106.930 3.620 ;
        RECT 105.525 2.410 107.425 2.640 ;
        RECT 102.755 1.470 103.770 1.590 ;
        RECT 102.285 0.300 102.515 1.285 ;
        RECT 102.755 1.070 103.000 1.470 ;
        RECT 103.400 1.070 103.770 1.470 ;
        RECT 102.755 0.945 103.770 1.070 ;
        RECT 104.550 0.300 104.890 1.990 ;
        RECT 105.930 1.770 106.870 2.150 ;
        RECT 107.195 1.450 107.425 2.410 ;
        RECT 107.765 2.595 107.995 3.110 ;
        RECT 108.430 2.830 108.770 3.620 ;
        RECT 109.125 3.160 111.675 3.390 ;
        RECT 113.070 3.335 113.410 3.620 ;
        RECT 109.125 2.595 109.355 3.160 ;
        RECT 107.765 2.365 109.355 2.595 ;
        RECT 109.125 1.830 109.355 2.365 ;
        RECT 105.625 1.220 107.425 1.450 ;
        RECT 105.625 0.765 105.855 1.220 ;
        RECT 106.590 0.300 106.930 0.990 ;
        RECT 107.195 0.940 107.425 1.220 ;
        RECT 107.665 1.595 109.355 1.830 ;
        RECT 107.665 1.210 107.895 1.595 ;
        RECT 108.125 1.035 109.400 1.270 ;
        RECT 109.850 1.210 110.255 2.710 ;
        RECT 110.605 1.680 110.950 2.930 ;
        RECT 111.445 2.140 111.675 3.160 ;
        RECT 114.410 2.600 114.750 3.060 ;
        RECT 112.410 2.370 114.750 2.600 ;
        RECT 111.445 1.910 114.150 2.140 ;
        RECT 110.605 1.450 113.690 1.680 ;
        RECT 108.125 0.940 108.355 1.035 ;
        RECT 107.195 0.705 108.355 0.940 ;
        RECT 109.170 0.760 109.400 1.035 ;
        RECT 110.890 0.990 111.230 1.450 ;
        RECT 108.585 0.300 108.815 0.735 ;
        RECT 109.170 0.530 111.870 0.760 ;
        RECT 112.910 0.300 113.250 1.220 ;
        RECT 113.920 0.760 114.150 1.910 ;
        RECT 114.405 0.990 114.750 2.370 ;
        RECT 115.000 0.760 115.230 2.695 ;
        RECT 115.530 2.025 115.870 3.060 ;
        RECT 117.765 2.815 117.995 3.620 ;
        RECT 118.885 2.520 119.150 3.165 ;
        RECT 119.705 3.030 119.935 3.620 ;
        RECT 117.050 2.420 119.150 2.520 ;
        RECT 117.050 2.290 120.375 2.420 ;
        RECT 118.925 2.080 120.375 2.290 ;
        RECT 115.530 1.790 118.630 2.025 ;
        RECT 115.530 0.990 115.870 1.790 ;
        RECT 113.920 0.530 116.610 0.760 ;
        RECT 117.905 0.300 118.135 1.285 ;
        RECT 118.925 0.890 119.155 2.080 ;
        RECT 120.750 1.590 121.130 3.370 ;
        RECT 121.910 2.735 122.250 3.620 ;
        RECT 122.885 2.640 123.115 3.110 ;
        RECT 123.950 2.870 124.290 3.620 ;
        RECT 122.885 2.410 124.785 2.640 ;
        RECT 120.115 1.470 121.130 1.590 ;
        RECT 119.645 0.300 119.875 1.285 ;
        RECT 120.115 1.070 120.360 1.470 ;
        RECT 120.760 1.070 121.130 1.470 ;
        RECT 120.115 0.945 121.130 1.070 ;
        RECT 121.910 0.300 122.250 1.990 ;
        RECT 123.290 1.770 124.230 2.150 ;
        RECT 124.555 1.450 124.785 2.410 ;
        RECT 125.125 2.595 125.355 3.110 ;
        RECT 125.790 2.830 126.130 3.620 ;
        RECT 126.485 3.160 129.035 3.390 ;
        RECT 130.430 3.335 130.770 3.620 ;
        RECT 126.485 2.595 126.715 3.160 ;
        RECT 125.125 2.365 126.715 2.595 ;
        RECT 126.485 1.830 126.715 2.365 ;
        RECT 122.985 1.220 124.785 1.450 ;
        RECT 122.985 0.765 123.215 1.220 ;
        RECT 123.950 0.300 124.290 0.990 ;
        RECT 124.555 0.940 124.785 1.220 ;
        RECT 125.025 1.595 126.715 1.830 ;
        RECT 125.025 1.210 125.255 1.595 ;
        RECT 125.485 1.035 126.760 1.270 ;
        RECT 127.210 1.210 127.615 2.710 ;
        RECT 127.965 1.680 128.310 2.930 ;
        RECT 128.805 2.140 129.035 3.160 ;
        RECT 131.770 2.600 132.110 3.060 ;
        RECT 129.770 2.370 132.110 2.600 ;
        RECT 128.805 1.910 131.510 2.140 ;
        RECT 127.965 1.450 131.050 1.680 ;
        RECT 125.485 0.940 125.715 1.035 ;
        RECT 124.555 0.705 125.715 0.940 ;
        RECT 126.530 0.760 126.760 1.035 ;
        RECT 128.250 0.990 128.590 1.450 ;
        RECT 125.945 0.300 126.175 0.735 ;
        RECT 126.530 0.530 129.230 0.760 ;
        RECT 130.270 0.300 130.610 1.220 ;
        RECT 131.280 0.760 131.510 1.910 ;
        RECT 131.765 0.990 132.110 2.370 ;
        RECT 132.360 0.760 132.590 2.695 ;
        RECT 132.890 2.025 133.230 3.060 ;
        RECT 135.125 2.815 135.355 3.620 ;
        RECT 136.245 2.520 136.510 3.165 ;
        RECT 137.065 3.030 137.295 3.620 ;
        RECT 134.410 2.420 136.510 2.520 ;
        RECT 134.410 2.290 137.735 2.420 ;
        RECT 136.285 2.080 137.735 2.290 ;
        RECT 132.890 1.790 135.990 2.025 ;
        RECT 132.890 0.990 133.230 1.790 ;
        RECT 131.280 0.530 133.970 0.760 ;
        RECT 135.265 0.300 135.495 1.285 ;
        RECT 136.285 0.890 136.515 2.080 ;
        RECT 138.110 1.590 138.490 3.370 ;
        RECT 139.270 2.735 139.610 3.620 ;
        RECT 140.245 2.640 140.475 3.110 ;
        RECT 141.310 2.870 141.650 3.620 ;
        RECT 140.245 2.410 142.145 2.640 ;
        RECT 137.475 1.470 138.490 1.590 ;
        RECT 137.005 0.300 137.235 1.285 ;
        RECT 137.475 1.070 137.720 1.470 ;
        RECT 138.120 1.070 138.490 1.470 ;
        RECT 137.475 0.945 138.490 1.070 ;
        RECT 139.270 0.300 139.610 1.990 ;
        RECT 140.650 1.770 141.590 2.150 ;
        RECT 141.915 1.450 142.145 2.410 ;
        RECT 142.485 2.595 142.715 3.110 ;
        RECT 143.150 2.830 143.490 3.620 ;
        RECT 143.845 3.160 146.395 3.390 ;
        RECT 147.790 3.335 148.130 3.620 ;
        RECT 143.845 2.595 144.075 3.160 ;
        RECT 142.485 2.365 144.075 2.595 ;
        RECT 143.845 1.830 144.075 2.365 ;
        RECT 140.345 1.220 142.145 1.450 ;
        RECT 140.345 0.765 140.575 1.220 ;
        RECT 141.310 0.300 141.650 0.990 ;
        RECT 141.915 0.940 142.145 1.220 ;
        RECT 142.385 1.595 144.075 1.830 ;
        RECT 142.385 1.210 142.615 1.595 ;
        RECT 142.845 1.035 144.120 1.270 ;
        RECT 144.570 1.210 144.975 2.710 ;
        RECT 145.325 1.680 145.670 2.930 ;
        RECT 146.165 2.140 146.395 3.160 ;
        RECT 149.130 2.600 149.470 3.060 ;
        RECT 147.130 2.370 149.470 2.600 ;
        RECT 146.165 1.910 148.870 2.140 ;
        RECT 145.325 1.450 148.410 1.680 ;
        RECT 142.845 0.940 143.075 1.035 ;
        RECT 141.915 0.705 143.075 0.940 ;
        RECT 143.890 0.760 144.120 1.035 ;
        RECT 145.610 0.990 145.950 1.450 ;
        RECT 143.305 0.300 143.535 0.735 ;
        RECT 143.890 0.530 146.590 0.760 ;
        RECT 147.630 0.300 147.970 1.220 ;
        RECT 148.640 0.760 148.870 1.910 ;
        RECT 149.125 0.990 149.470 2.370 ;
        RECT 149.720 0.760 149.950 2.695 ;
        RECT 150.250 2.025 150.590 3.060 ;
        RECT 152.485 2.815 152.715 3.620 ;
        RECT 153.605 2.520 153.870 3.165 ;
        RECT 154.425 3.030 154.655 3.620 ;
        RECT 151.770 2.420 153.870 2.520 ;
        RECT 151.770 2.290 155.095 2.420 ;
        RECT 153.645 2.080 155.095 2.290 ;
        RECT 150.250 1.790 153.350 2.025 ;
        RECT 150.250 0.990 150.590 1.790 ;
        RECT 148.640 0.530 151.330 0.760 ;
        RECT 152.625 0.300 152.855 1.285 ;
        RECT 153.645 0.890 153.875 2.080 ;
        RECT 155.470 1.590 155.850 3.370 ;
        RECT 156.630 2.735 156.970 3.620 ;
        RECT 157.605 2.640 157.835 3.110 ;
        RECT 158.670 2.870 159.010 3.620 ;
        RECT 157.605 2.410 159.505 2.640 ;
        RECT 154.835 1.470 155.850 1.590 ;
        RECT 154.365 0.300 154.595 1.285 ;
        RECT 154.835 1.070 155.080 1.470 ;
        RECT 155.480 1.070 155.850 1.470 ;
        RECT 154.835 0.945 155.850 1.070 ;
        RECT 156.630 0.300 156.970 1.990 ;
        RECT 158.010 1.770 158.950 2.150 ;
        RECT 159.275 1.450 159.505 2.410 ;
        RECT 159.845 2.595 160.075 3.110 ;
        RECT 160.510 2.830 160.850 3.620 ;
        RECT 161.205 3.160 163.755 3.390 ;
        RECT 165.150 3.335 165.490 3.620 ;
        RECT 161.205 2.595 161.435 3.160 ;
        RECT 159.845 2.365 161.435 2.595 ;
        RECT 161.205 1.830 161.435 2.365 ;
        RECT 157.705 1.220 159.505 1.450 ;
        RECT 157.705 0.765 157.935 1.220 ;
        RECT 158.670 0.300 159.010 0.990 ;
        RECT 159.275 0.940 159.505 1.220 ;
        RECT 159.745 1.595 161.435 1.830 ;
        RECT 159.745 1.210 159.975 1.595 ;
        RECT 160.205 1.035 161.480 1.270 ;
        RECT 161.930 1.210 162.335 2.710 ;
        RECT 162.685 1.680 163.030 2.930 ;
        RECT 163.525 2.140 163.755 3.160 ;
        RECT 166.490 2.600 166.830 3.060 ;
        RECT 164.490 2.370 166.830 2.600 ;
        RECT 163.525 1.910 166.230 2.140 ;
        RECT 162.685 1.450 165.770 1.680 ;
        RECT 160.205 0.940 160.435 1.035 ;
        RECT 159.275 0.705 160.435 0.940 ;
        RECT 161.250 0.760 161.480 1.035 ;
        RECT 162.970 0.990 163.310 1.450 ;
        RECT 160.665 0.300 160.895 0.735 ;
        RECT 161.250 0.530 163.950 0.760 ;
        RECT 164.990 0.300 165.330 1.220 ;
        RECT 166.000 0.760 166.230 1.910 ;
        RECT 166.485 0.990 166.830 2.370 ;
        RECT 167.080 0.760 167.310 2.695 ;
        RECT 167.610 2.025 167.950 3.060 ;
        RECT 169.845 2.815 170.075 3.620 ;
        RECT 170.965 2.520 171.230 3.165 ;
        RECT 171.785 3.030 172.015 3.620 ;
        RECT 169.130 2.420 171.230 2.520 ;
        RECT 169.130 2.290 172.455 2.420 ;
        RECT 171.005 2.080 172.455 2.290 ;
        RECT 167.610 1.790 170.710 2.025 ;
        RECT 167.610 0.990 167.950 1.790 ;
        RECT 166.000 0.530 168.690 0.760 ;
        RECT 169.985 0.300 170.215 1.285 ;
        RECT 171.005 0.890 171.235 2.080 ;
        RECT 172.830 1.590 173.210 3.370 ;
        RECT 173.990 2.735 174.330 3.620 ;
        RECT 174.965 2.640 175.195 3.110 ;
        RECT 176.030 2.870 176.370 3.620 ;
        RECT 174.965 2.410 176.865 2.640 ;
        RECT 172.195 1.470 173.210 1.590 ;
        RECT 171.725 0.300 171.955 1.285 ;
        RECT 172.195 1.070 172.440 1.470 ;
        RECT 172.840 1.070 173.210 1.470 ;
        RECT 172.195 0.945 173.210 1.070 ;
        RECT 173.990 0.300 174.330 1.990 ;
        RECT 175.370 1.770 176.310 2.150 ;
        RECT 176.635 1.450 176.865 2.410 ;
        RECT 177.205 2.595 177.435 3.110 ;
        RECT 177.870 2.830 178.210 3.620 ;
        RECT 178.565 3.160 181.115 3.390 ;
        RECT 182.510 3.335 182.850 3.620 ;
        RECT 178.565 2.595 178.795 3.160 ;
        RECT 177.205 2.365 178.795 2.595 ;
        RECT 178.565 1.830 178.795 2.365 ;
        RECT 175.065 1.220 176.865 1.450 ;
        RECT 175.065 0.765 175.295 1.220 ;
        RECT 176.030 0.300 176.370 0.990 ;
        RECT 176.635 0.940 176.865 1.220 ;
        RECT 177.105 1.595 178.795 1.830 ;
        RECT 177.105 1.210 177.335 1.595 ;
        RECT 177.565 1.035 178.840 1.270 ;
        RECT 179.290 1.210 179.695 2.710 ;
        RECT 180.045 1.680 180.390 2.930 ;
        RECT 180.885 2.140 181.115 3.160 ;
        RECT 183.850 2.600 184.190 3.060 ;
        RECT 181.850 2.370 184.190 2.600 ;
        RECT 180.885 1.910 183.590 2.140 ;
        RECT 180.045 1.450 183.130 1.680 ;
        RECT 177.565 0.940 177.795 1.035 ;
        RECT 176.635 0.705 177.795 0.940 ;
        RECT 178.610 0.760 178.840 1.035 ;
        RECT 180.330 0.990 180.670 1.450 ;
        RECT 178.025 0.300 178.255 0.735 ;
        RECT 178.610 0.530 181.310 0.760 ;
        RECT 182.350 0.300 182.690 1.220 ;
        RECT 183.360 0.760 183.590 1.910 ;
        RECT 183.845 0.990 184.190 2.370 ;
        RECT 184.440 0.760 184.670 2.695 ;
        RECT 184.970 2.025 185.310 3.060 ;
        RECT 187.205 2.815 187.435 3.620 ;
        RECT 188.325 2.520 188.590 3.165 ;
        RECT 189.145 3.030 189.375 3.620 ;
        RECT 186.490 2.420 188.590 2.520 ;
        RECT 186.490 2.290 189.815 2.420 ;
        RECT 188.365 2.080 189.815 2.290 ;
        RECT 184.970 1.790 188.070 2.025 ;
        RECT 184.970 0.990 185.310 1.790 ;
        RECT 183.360 0.530 186.050 0.760 ;
        RECT 187.345 0.300 187.575 1.285 ;
        RECT 188.365 0.890 188.595 2.080 ;
        RECT 190.190 1.590 190.570 3.370 ;
        RECT 191.350 2.735 191.690 3.620 ;
        RECT 192.325 2.640 192.555 3.110 ;
        RECT 193.390 2.870 193.730 3.620 ;
        RECT 192.325 2.410 194.225 2.640 ;
        RECT 189.555 1.470 190.570 1.590 ;
        RECT 189.085 0.300 189.315 1.285 ;
        RECT 189.555 1.070 189.800 1.470 ;
        RECT 190.200 1.070 190.570 1.470 ;
        RECT 189.555 0.945 190.570 1.070 ;
        RECT 191.350 0.300 191.690 1.990 ;
        RECT 192.730 1.770 193.670 2.150 ;
        RECT 193.995 1.450 194.225 2.410 ;
        RECT 194.565 2.595 194.795 3.110 ;
        RECT 195.230 2.830 195.570 3.620 ;
        RECT 195.925 3.160 198.475 3.390 ;
        RECT 199.870 3.335 200.210 3.620 ;
        RECT 195.925 2.595 196.155 3.160 ;
        RECT 194.565 2.365 196.155 2.595 ;
        RECT 195.925 1.830 196.155 2.365 ;
        RECT 192.425 1.220 194.225 1.450 ;
        RECT 192.425 0.765 192.655 1.220 ;
        RECT 193.390 0.300 193.730 0.990 ;
        RECT 193.995 0.940 194.225 1.220 ;
        RECT 194.465 1.595 196.155 1.830 ;
        RECT 194.465 1.210 194.695 1.595 ;
        RECT 194.925 1.035 196.200 1.270 ;
        RECT 196.650 1.210 197.055 2.710 ;
        RECT 197.405 1.680 197.750 2.930 ;
        RECT 198.245 2.140 198.475 3.160 ;
        RECT 201.210 2.600 201.550 3.060 ;
        RECT 199.210 2.370 201.550 2.600 ;
        RECT 198.245 1.910 200.950 2.140 ;
        RECT 197.405 1.450 200.490 1.680 ;
        RECT 194.925 0.940 195.155 1.035 ;
        RECT 193.995 0.705 195.155 0.940 ;
        RECT 195.970 0.760 196.200 1.035 ;
        RECT 197.690 0.990 198.030 1.450 ;
        RECT 195.385 0.300 195.615 0.735 ;
        RECT 195.970 0.530 198.670 0.760 ;
        RECT 199.710 0.300 200.050 1.220 ;
        RECT 200.720 0.760 200.950 1.910 ;
        RECT 201.205 0.990 201.550 2.370 ;
        RECT 201.800 0.760 202.030 2.695 ;
        RECT 202.330 2.025 202.670 3.060 ;
        RECT 204.565 2.815 204.795 3.620 ;
        RECT 205.685 2.520 205.950 3.165 ;
        RECT 206.505 3.030 206.735 3.620 ;
        RECT 203.850 2.420 205.950 2.520 ;
        RECT 203.850 2.290 207.175 2.420 ;
        RECT 205.725 2.080 207.175 2.290 ;
        RECT 202.330 1.790 205.430 2.025 ;
        RECT 202.330 0.990 202.670 1.790 ;
        RECT 200.720 0.530 203.410 0.760 ;
        RECT 204.705 0.300 204.935 1.285 ;
        RECT 205.725 0.890 205.955 2.080 ;
        RECT 207.550 1.590 207.930 3.370 ;
        RECT 208.710 2.735 209.050 3.620 ;
        RECT 209.685 2.640 209.915 3.110 ;
        RECT 210.750 2.870 211.090 3.620 ;
        RECT 209.685 2.410 211.585 2.640 ;
        RECT 206.915 1.470 207.930 1.590 ;
        RECT 206.445 0.300 206.675 1.285 ;
        RECT 206.915 1.070 207.160 1.470 ;
        RECT 207.560 1.070 207.930 1.470 ;
        RECT 206.915 0.945 207.930 1.070 ;
        RECT 208.710 0.300 209.050 1.990 ;
        RECT 210.090 1.770 211.030 2.150 ;
        RECT 211.355 1.450 211.585 2.410 ;
        RECT 211.925 2.595 212.155 3.110 ;
        RECT 212.590 2.830 212.930 3.620 ;
        RECT 213.285 3.160 215.835 3.390 ;
        RECT 217.230 3.335 217.570 3.620 ;
        RECT 213.285 2.595 213.515 3.160 ;
        RECT 211.925 2.365 213.515 2.595 ;
        RECT 213.285 1.830 213.515 2.365 ;
        RECT 209.785 1.220 211.585 1.450 ;
        RECT 209.785 0.765 210.015 1.220 ;
        RECT 210.750 0.300 211.090 0.990 ;
        RECT 211.355 0.940 211.585 1.220 ;
        RECT 211.825 1.595 213.515 1.830 ;
        RECT 211.825 1.210 212.055 1.595 ;
        RECT 212.285 1.035 213.560 1.270 ;
        RECT 214.010 1.210 214.415 2.710 ;
        RECT 214.765 1.680 215.110 2.930 ;
        RECT 215.605 2.140 215.835 3.160 ;
        RECT 218.570 2.600 218.910 3.060 ;
        RECT 216.570 2.370 218.910 2.600 ;
        RECT 215.605 1.910 218.310 2.140 ;
        RECT 214.765 1.450 217.850 1.680 ;
        RECT 212.285 0.940 212.515 1.035 ;
        RECT 211.355 0.705 212.515 0.940 ;
        RECT 213.330 0.760 213.560 1.035 ;
        RECT 215.050 0.990 215.390 1.450 ;
        RECT 212.745 0.300 212.975 0.735 ;
        RECT 213.330 0.530 216.030 0.760 ;
        RECT 217.070 0.300 217.410 1.220 ;
        RECT 218.080 0.760 218.310 1.910 ;
        RECT 218.565 0.990 218.910 2.370 ;
        RECT 219.160 0.760 219.390 2.695 ;
        RECT 219.690 2.025 220.030 3.060 ;
        RECT 221.925 2.815 222.155 3.620 ;
        RECT 223.045 2.520 223.310 3.165 ;
        RECT 223.865 3.030 224.095 3.620 ;
        RECT 221.210 2.420 223.310 2.520 ;
        RECT 221.210 2.290 224.535 2.420 ;
        RECT 223.085 2.080 224.535 2.290 ;
        RECT 219.690 1.790 222.790 2.025 ;
        RECT 219.690 0.990 220.030 1.790 ;
        RECT 218.080 0.530 220.770 0.760 ;
        RECT 222.065 0.300 222.295 1.285 ;
        RECT 223.085 0.890 223.315 2.080 ;
        RECT 224.910 1.590 225.290 3.370 ;
        RECT 226.070 2.735 226.410 3.620 ;
        RECT 227.045 2.640 227.275 3.110 ;
        RECT 228.110 2.870 228.450 3.620 ;
        RECT 227.045 2.410 228.945 2.640 ;
        RECT 224.275 1.470 225.290 1.590 ;
        RECT 223.805 0.300 224.035 1.285 ;
        RECT 224.275 1.070 224.520 1.470 ;
        RECT 224.920 1.070 225.290 1.470 ;
        RECT 224.275 0.945 225.290 1.070 ;
        RECT 226.070 0.300 226.410 1.990 ;
        RECT 227.450 1.770 228.390 2.150 ;
        RECT 228.715 1.450 228.945 2.410 ;
        RECT 229.285 2.595 229.515 3.110 ;
        RECT 229.950 2.830 230.290 3.620 ;
        RECT 230.645 3.160 233.195 3.390 ;
        RECT 234.590 3.335 234.930 3.620 ;
        RECT 230.645 2.595 230.875 3.160 ;
        RECT 229.285 2.365 230.875 2.595 ;
        RECT 230.645 1.830 230.875 2.365 ;
        RECT 227.145 1.220 228.945 1.450 ;
        RECT 227.145 0.765 227.375 1.220 ;
        RECT 228.110 0.300 228.450 0.990 ;
        RECT 228.715 0.940 228.945 1.220 ;
        RECT 229.185 1.595 230.875 1.830 ;
        RECT 229.185 1.210 229.415 1.595 ;
        RECT 229.645 1.035 230.920 1.270 ;
        RECT 231.370 1.210 231.775 2.710 ;
        RECT 232.125 1.680 232.470 2.930 ;
        RECT 232.965 2.140 233.195 3.160 ;
        RECT 235.930 2.600 236.270 3.060 ;
        RECT 233.930 2.370 236.270 2.600 ;
        RECT 232.965 1.910 235.670 2.140 ;
        RECT 232.125 1.450 235.210 1.680 ;
        RECT 229.645 0.940 229.875 1.035 ;
        RECT 228.715 0.705 229.875 0.940 ;
        RECT 230.690 0.760 230.920 1.035 ;
        RECT 232.410 0.990 232.750 1.450 ;
        RECT 230.105 0.300 230.335 0.735 ;
        RECT 230.690 0.530 233.390 0.760 ;
        RECT 234.430 0.300 234.770 1.220 ;
        RECT 235.440 0.760 235.670 1.910 ;
        RECT 235.925 0.990 236.270 2.370 ;
        RECT 236.520 0.760 236.750 2.695 ;
        RECT 237.050 2.025 237.390 3.060 ;
        RECT 239.285 2.815 239.515 3.620 ;
        RECT 240.405 2.520 240.670 3.165 ;
        RECT 241.225 3.030 241.455 3.620 ;
        RECT 238.570 2.420 240.670 2.520 ;
        RECT 238.570 2.290 241.895 2.420 ;
        RECT 240.445 2.080 241.895 2.290 ;
        RECT 237.050 1.790 240.150 2.025 ;
        RECT 237.050 0.990 237.390 1.790 ;
        RECT 235.440 0.530 238.130 0.760 ;
        RECT 239.425 0.300 239.655 1.285 ;
        RECT 240.445 0.890 240.675 2.080 ;
        RECT 242.270 1.590 242.650 3.370 ;
        RECT 243.430 2.735 243.770 3.620 ;
        RECT 244.405 2.640 244.635 3.110 ;
        RECT 245.470 2.870 245.810 3.620 ;
        RECT 244.405 2.410 246.305 2.640 ;
        RECT 241.635 1.470 242.650 1.590 ;
        RECT 241.165 0.300 241.395 1.285 ;
        RECT 241.635 1.070 241.880 1.470 ;
        RECT 242.280 1.070 242.650 1.470 ;
        RECT 241.635 0.945 242.650 1.070 ;
        RECT 243.430 0.300 243.770 1.990 ;
        RECT 244.810 1.770 245.750 2.150 ;
        RECT 246.075 1.450 246.305 2.410 ;
        RECT 246.645 2.595 246.875 3.110 ;
        RECT 247.310 2.830 247.650 3.620 ;
        RECT 248.005 3.160 250.555 3.390 ;
        RECT 251.950 3.335 252.290 3.620 ;
        RECT 248.005 2.595 248.235 3.160 ;
        RECT 246.645 2.365 248.235 2.595 ;
        RECT 248.005 1.830 248.235 2.365 ;
        RECT 244.505 1.220 246.305 1.450 ;
        RECT 244.505 0.765 244.735 1.220 ;
        RECT 245.470 0.300 245.810 0.990 ;
        RECT 246.075 0.940 246.305 1.220 ;
        RECT 246.545 1.595 248.235 1.830 ;
        RECT 246.545 1.210 246.775 1.595 ;
        RECT 247.005 1.035 248.280 1.270 ;
        RECT 248.730 1.210 249.135 2.710 ;
        RECT 249.485 1.680 249.830 2.930 ;
        RECT 250.325 2.140 250.555 3.160 ;
        RECT 253.290 2.600 253.630 3.060 ;
        RECT 251.290 2.370 253.630 2.600 ;
        RECT 250.325 1.910 253.030 2.140 ;
        RECT 249.485 1.450 252.570 1.680 ;
        RECT 247.005 0.940 247.235 1.035 ;
        RECT 246.075 0.705 247.235 0.940 ;
        RECT 248.050 0.760 248.280 1.035 ;
        RECT 249.770 0.990 250.110 1.450 ;
        RECT 247.465 0.300 247.695 0.735 ;
        RECT 248.050 0.530 250.750 0.760 ;
        RECT 251.790 0.300 252.130 1.220 ;
        RECT 252.800 0.760 253.030 1.910 ;
        RECT 253.285 0.990 253.630 2.370 ;
        RECT 253.880 0.760 254.110 2.695 ;
        RECT 254.410 2.025 254.750 3.060 ;
        RECT 256.645 2.815 256.875 3.620 ;
        RECT 257.765 2.520 258.030 3.165 ;
        RECT 258.585 3.030 258.815 3.620 ;
        RECT 255.930 2.420 258.030 2.520 ;
        RECT 255.930 2.290 259.255 2.420 ;
        RECT 257.805 2.080 259.255 2.290 ;
        RECT 254.410 1.790 257.510 2.025 ;
        RECT 254.410 0.990 254.750 1.790 ;
        RECT 252.800 0.530 255.490 0.760 ;
        RECT 256.785 0.300 257.015 1.285 ;
        RECT 257.805 0.890 258.035 2.080 ;
        RECT 259.630 1.590 260.010 3.370 ;
        RECT 260.790 2.735 261.130 3.620 ;
        RECT 261.765 2.640 261.995 3.110 ;
        RECT 262.830 2.870 263.170 3.620 ;
        RECT 261.765 2.410 263.665 2.640 ;
        RECT 258.995 1.470 260.010 1.590 ;
        RECT 258.525 0.300 258.755 1.285 ;
        RECT 258.995 1.070 259.240 1.470 ;
        RECT 259.640 1.070 260.010 1.470 ;
        RECT 258.995 0.945 260.010 1.070 ;
        RECT 260.790 0.300 261.130 1.990 ;
        RECT 262.170 1.770 263.110 2.150 ;
        RECT 263.435 1.450 263.665 2.410 ;
        RECT 264.005 2.595 264.235 3.110 ;
        RECT 264.670 2.830 265.010 3.620 ;
        RECT 265.365 3.160 267.915 3.390 ;
        RECT 269.310 3.335 269.650 3.620 ;
        RECT 265.365 2.595 265.595 3.160 ;
        RECT 264.005 2.365 265.595 2.595 ;
        RECT 265.365 1.830 265.595 2.365 ;
        RECT 261.865 1.220 263.665 1.450 ;
        RECT 261.865 0.765 262.095 1.220 ;
        RECT 262.830 0.300 263.170 0.990 ;
        RECT 263.435 0.940 263.665 1.220 ;
        RECT 263.905 1.595 265.595 1.830 ;
        RECT 263.905 1.210 264.135 1.595 ;
        RECT 264.365 1.035 265.640 1.270 ;
        RECT 266.090 1.210 266.495 2.710 ;
        RECT 266.845 1.680 267.190 2.930 ;
        RECT 267.685 2.140 267.915 3.160 ;
        RECT 270.650 2.600 270.990 3.060 ;
        RECT 268.650 2.370 270.990 2.600 ;
        RECT 267.685 1.910 270.390 2.140 ;
        RECT 266.845 1.450 269.930 1.680 ;
        RECT 264.365 0.940 264.595 1.035 ;
        RECT 263.435 0.705 264.595 0.940 ;
        RECT 265.410 0.760 265.640 1.035 ;
        RECT 267.130 0.990 267.470 1.450 ;
        RECT 264.825 0.300 265.055 0.735 ;
        RECT 265.410 0.530 268.110 0.760 ;
        RECT 269.150 0.300 269.490 1.220 ;
        RECT 270.160 0.760 270.390 1.910 ;
        RECT 270.645 0.990 270.990 2.370 ;
        RECT 271.240 0.760 271.470 2.695 ;
        RECT 271.770 2.025 272.110 3.060 ;
        RECT 274.005 2.815 274.235 3.620 ;
        RECT 275.125 2.520 275.390 3.165 ;
        RECT 275.945 3.030 276.175 3.620 ;
        RECT 273.290 2.420 275.390 2.520 ;
        RECT 273.290 2.290 276.615 2.420 ;
        RECT 275.165 2.080 276.615 2.290 ;
        RECT 271.770 1.790 274.870 2.025 ;
        RECT 271.770 0.990 272.110 1.790 ;
        RECT 270.160 0.530 272.850 0.760 ;
        RECT 274.145 0.300 274.375 1.285 ;
        RECT 275.165 0.890 275.395 2.080 ;
        RECT 276.990 1.590 277.370 3.370 ;
        RECT 278.150 2.735 278.490 3.620 ;
        RECT 279.250 2.730 279.590 3.620 ;
        RECT 276.355 1.470 277.370 1.590 ;
        RECT 275.885 0.300 276.115 1.285 ;
        RECT 276.355 1.070 276.600 1.470 ;
        RECT 277.000 1.070 277.370 1.470 ;
        RECT 276.355 0.945 277.370 1.070 ;
        RECT 278.150 0.300 278.490 1.990 ;
        RECT 279.250 0.300 279.590 2.000 ;
        RECT 0.000 -0.300 280.000 0.300 ;
      LAYER Metal2 ;
        RECT 0.300 -0.270 0.720 8.110 ;
        RECT 13.340 6.230 20.000 6.650 ;
        RECT 13.340 2.630 13.760 6.230 ;
        RECT 19.580 5.050 20.000 6.230 ;
        RECT 30.700 6.230 37.360 6.650 ;
        RECT 30.700 2.630 31.120 6.230 ;
        RECT 36.940 5.050 37.360 6.230 ;
        RECT 48.060 6.230 54.720 6.650 ;
        RECT 48.060 2.630 48.480 6.230 ;
        RECT 54.300 5.050 54.720 6.230 ;
        RECT 65.420 6.230 72.080 6.650 ;
        RECT 65.420 2.630 65.840 6.230 ;
        RECT 71.660 5.050 72.080 6.230 ;
        RECT 82.780 6.230 89.440 6.650 ;
        RECT 82.780 2.630 83.200 6.230 ;
        RECT 89.020 5.050 89.440 6.230 ;
        RECT 100.140 6.230 106.800 6.650 ;
        RECT 100.140 2.630 100.560 6.230 ;
        RECT 106.380 5.050 106.800 6.230 ;
        RECT 117.500 6.230 124.160 6.650 ;
        RECT 117.500 2.630 117.920 6.230 ;
        RECT 123.740 5.050 124.160 6.230 ;
        RECT 134.860 6.230 141.520 6.650 ;
        RECT 134.860 2.630 135.280 6.230 ;
        RECT 141.100 5.050 141.520 6.230 ;
        RECT 152.220 6.230 158.880 6.650 ;
        RECT 152.220 2.630 152.640 6.230 ;
        RECT 158.460 5.050 158.880 6.230 ;
        RECT 169.580 6.230 176.240 6.650 ;
        RECT 169.580 2.630 170.000 6.230 ;
        RECT 175.820 5.050 176.240 6.230 ;
        RECT 186.940 6.230 193.600 6.650 ;
        RECT 186.940 2.630 187.360 6.230 ;
        RECT 193.180 5.050 193.600 6.230 ;
        RECT 204.300 6.230 210.960 6.650 ;
        RECT 204.300 2.630 204.720 6.230 ;
        RECT 210.540 5.050 210.960 6.230 ;
        RECT 221.660 6.230 228.320 6.650 ;
        RECT 221.660 2.630 222.080 6.230 ;
        RECT 227.900 5.050 228.320 6.230 ;
        RECT 239.020 6.230 245.680 6.650 ;
        RECT 239.020 2.630 239.440 6.230 ;
        RECT 245.260 5.050 245.680 6.230 ;
        RECT 256.380 6.230 263.040 6.650 ;
        RECT 256.380 2.630 256.800 6.230 ;
        RECT 262.620 5.050 263.040 6.230 ;
        RECT 273.740 6.230 274.260 6.650 ;
        RECT 273.740 2.630 274.160 6.230 ;
        RECT 1.980 1.820 2.400 2.230 ;
        RECT 5.620 2.210 13.760 2.630 ;
        RECT 19.340 1.820 19.760 2.230 ;
        RECT 22.980 2.210 31.120 2.630 ;
        RECT 36.700 1.820 37.120 2.230 ;
        RECT 40.340 2.210 48.480 2.630 ;
        RECT 54.060 1.820 54.480 2.230 ;
        RECT 57.700 2.210 65.840 2.630 ;
        RECT 71.420 1.820 71.840 2.230 ;
        RECT 75.060 2.210 83.200 2.630 ;
        RECT 88.780 1.820 89.200 2.230 ;
        RECT 92.420 2.210 100.560 2.630 ;
        RECT 106.140 1.820 106.560 2.230 ;
        RECT 109.780 2.210 117.920 2.630 ;
        RECT 123.500 1.820 123.920 2.230 ;
        RECT 127.140 2.210 135.280 2.630 ;
        RECT 140.860 1.820 141.280 2.230 ;
        RECT 144.500 2.210 152.640 2.630 ;
        RECT 158.220 1.820 158.640 2.230 ;
        RECT 161.860 2.210 170.000 2.630 ;
        RECT 175.580 1.820 176.000 2.230 ;
        RECT 179.220 2.210 187.360 2.630 ;
        RECT 192.940 1.820 193.360 2.230 ;
        RECT 196.580 2.210 204.720 2.630 ;
        RECT 210.300 1.820 210.720 2.230 ;
        RECT 213.940 2.210 222.080 2.630 ;
        RECT 227.660 1.820 228.080 2.230 ;
        RECT 231.300 2.210 239.440 2.630 ;
        RECT 245.020 1.820 245.440 2.230 ;
        RECT 248.660 2.210 256.800 2.630 ;
        RECT 262.380 1.820 262.800 2.230 ;
        RECT 266.020 2.210 274.160 2.630 ;
        RECT 1.980 1.720 262.800 1.820 ;
        RECT 1.980 1.500 135.000 1.720 ;
        RECT 135.400 1.500 262.800 1.720 ;
        RECT 1.980 1.400 262.800 1.500 ;
  END
END medium_line
END LIBRARY

